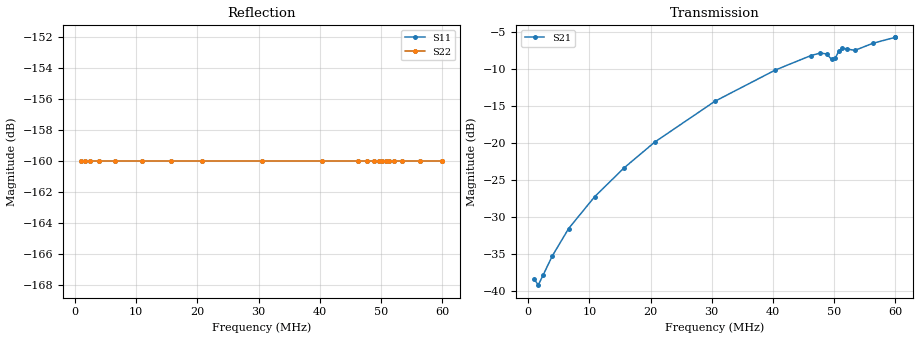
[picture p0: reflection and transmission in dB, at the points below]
! ListType=Lin
!!2 x 2 x FT290-43 mit 2 x 2 x 6 Windungen mit AWG12 mit Ueberschlag
# MHZ S RI R 50
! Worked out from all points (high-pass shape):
!   1000 points, 1 MHz to 60 MHz, reference 50 ohm
!   highest |S21| = -5.75 dB at 59.94 MHz (marker M1); lowest = -39.3 dB at 1.65 MHz (marker M2)
!   |S21| within 3 dB of the highest: 44.44 MHz to 49.64 MHz (5.199 MHz wide, 11.1 % of centre); 50.04 MHz to end of sweep
!   lowest |S11| = - dB at 1 MHz (marker M3), VSWR 1.00, Z = 50 + j0 ohm
!   |S11| at or under -10 dB: start of sweep to end of sweep
!   S12 and S22 are empty: the file has one direction only
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1  0 0  -0.000513 0.012  0 0  0 0
1.64965  0 0  -0.000738 0.0109  0 0  0 0
2.417417  0 0  -0.000527 0.0127  0 0  0 0
3.952953  0 0  -0.000612 0.0172  0 0  0 0
6.610611  0 0  -0.0013 0.0263  0 0  0 0
10.86286  0 0  -0.00526 0.0429  0 0  0 0
15.64665  0 0  -0.0113 0.0666  0 0  0 0
20.66667  0 0  -0.0168 0.0996  0 0  0 0
30.52953  0 0  -0.00926 0.1908  0 0  0 0
40.39239  0 0  0.0608 0.3044  0 0  0 0
46.18018  0 0  0.1564 0.3554  0 0  0 0
47.65666  0 0  0.1917 0.3554  0 0  0 0
48.77878  0 0  0.2173 0.3348  0 0  0 0
49.60561  0 0  0.201 0.306  0 0  0 0
50.1962  0 0  0.1718 0.3321  0 0  0 0
50.78679  0 0  0.1951 0.3691  0 0  0 0
51.31832  0 0  0.2274 0.3718  0 0  0 0
52.08609  0 0  0.2503 0.3512  0 0  0 0
53.38539  0 0  0.2466 0.3418  0 0  0 0
56.33834  0 0  0.2945 0.367  0 0  0 0
59.94094  0 0  0.3752 0.3541  0 0  0 0
60  0 0  0.3727 0.3562  0 0  0 0
